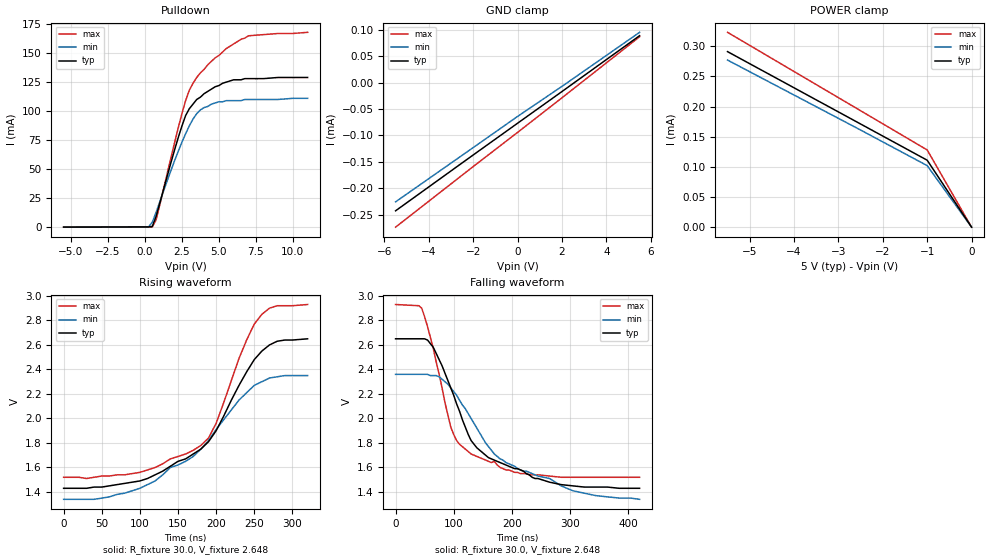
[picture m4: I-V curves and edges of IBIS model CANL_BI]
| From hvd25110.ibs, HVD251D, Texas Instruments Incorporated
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|   Driver (CANL) Output/Receiver Input Model
[Model]   CANL_BI
Model_type   I/O_open_drain
| Signals   CANH
Vinh = 0.9V
Vinl = 0.5V
Rref = 30   |Note: 60 Ohm differential load;
Vref = 2.3   |tr, tf measured in single ended configuration
| variable   typ   min   max
C_comp   1.0pF   NA   NA
|   typ   min   max
[Temperature Range]   25.0   -40   125
[Voltage Range]   5.0V   4.5V   5.5V
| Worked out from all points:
|   slope of the pulldown table from 0 to 0.75 V, typ, clamps not added: 84.4 ohm
|   rising waveform, R_fixture 30.0, V_fixture 2.648: 20-80 % time 81.6ns typ, 99.4ns min, 56.9ns max; typ from 1.43 V to 2.65 V
|   falling waveform, R_fixture 30.0, V_fixture 2.648: 20-80 % time 81ns typ, 129ns min, 47.3ns max; typ from 2.65 V to 1.43 V
[Pulldown]
|   Voltage   I(typ)   I(min)   I(max)
-5.5V     -243uA     -226uA     -274uA
250mV     -72.3uA    20.6uA     -87.7uA
500mV     382uA      4.06mA     -72.2uA
750mV     8.81mA     12.4mA     5.92mA
2.5V      87.1mA     73.1mA     97.8mA
3V        102mA      87.2mA     118mA
3.5V      110mA      97.7mA     129mA
4V        115mA      103mA      136mA
5V        122mA      108mA      148mA
6V        127mA      109mA      158mA
7V        128mA      110mA      165mA
11V       129mA      111mA      168mA
[Power_clamp]
| Note that the[POWER_clamp]voltage table is referenced to Vcc
| and is calculated using Vtable=Vcc - Vmeasured.
|   Voltage   I(typ)   I(min)   I(max)
-5.5V     291uA      277uA      323uA
-4V       231uA      219uA      258uA
-2.5V     171uA      161uA      193uA
-1V       111uA      102uA      128uA
0V        0A         0A         0A
[GND_clamp]
|   Voltage   I(typ)   I(min)   I(max)
-5.5V     -243uA     -226uA     -274uA
-2V       -137uA     -123uA     -159uA
0V        -76.8uA    -63.9uA    -94.2uA
2V        -16.7uA    -6.87uA    -28.6uA
5.5V      89.3uA     95.7uA     87.3uA
[Ramp]
|   typ   min   max
dV/dt_r   1.21/130ns   1.01/140ns   1.40/110ns
dV/dt_f   1.21/155ns   1.01/195ns   1.40/100ns
R_load = 30ohm  | Note: The measurement is single-ended with 30ohm
|   to Vfixture
[Rising Waveform]
R_fixture = 30.0
V_fixture = 2.648
V_fixture_min = 2.356
V_fixture_max = 2.927
C_fixture = 0p
L_fixture = 0n
|   V(typ)   V(min)   V(max)
0s        1.43V      1.34V      1.52V
40ns      1.44V      1.34V      1.52V
100ns     1.49V      1.43V      1.56V
180ns     1.75V      1.75V      1.78V
190ns     1.81V      1.82V      1.84V
200ns     1.9V       1.91V      1.96V
230ns     2.27V      2.15V      2.49V
250ns     2.48V      2.27V      2.77V
270ns     2.6V       2.33V      2.9V
320ns     2.65V      2.35V      2.93V
[Falling Waveform]
R_fixture = 30.0
V_fixture = 2.648
V_fixture_min = 2.356
V_fixture_max = 2.927
C_fixture = 0p
L_fixture = 0n
|   V(typ)   V(min)   V(max)
0s        2.65V      2.36V      2.93V
45ns      2.65V      2.36V      2.9V
65ns      2.58V      2.35V      2.57V
95ns      2.25V      2.25V      1.93V
105ns     2.12V      2.19V      1.82V
130ns     1.82V      2V         1.71V
170ns     1.66V      1.71V      1.65V
210ns     1.59V      1.59V      1.56V
285ns     1.46V      1.45V      1.52V
420ns     1.43V      1.34V      1.52V
